VERSION 5.7 ;
  NOWIREEXTENSIONATPIN ON ;
  DIVIDERCHAR "/" ;
  BUSBITCHARS "[]" ;
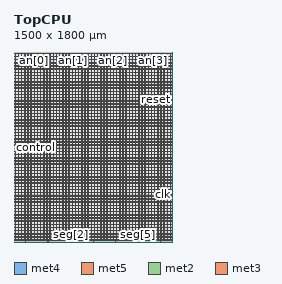
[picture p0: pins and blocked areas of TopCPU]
MACRO TopCPU
  CLASS BLOCK ;
  FOREIGN TopCPU ;
  ORIGIN 0.000 0.000 ;
  SIZE 1500.000 BY 1800.000 ;
  PIN VGND
    DIRECTION INOUT ;
    USE GROUND ;
    PORT
      LAYER met4 ;
        RECT 13.020 10.640 14.620 1787.280 ;
    END
    PORT
      LAYER met4 ;
        RECT 43.020 10.640 44.620 1787.280 ;
    END
    PORT
      LAYER met4 ;
        RECT 73.020 10.640 74.620 1787.280 ;
    END
    PORT
      LAYER met4 ;
        RECT 103.020 10.640 104.620 1787.280 ;
    END
    PORT
      LAYER met4 ;
        RECT 133.020 10.640 134.620 1787.280 ;
    END
    PORT
      LAYER met4 ;
        RECT 163.020 10.640 164.620 1787.280 ;
    END
    PORT
      LAYER met4 ;
        RECT 193.020 10.640 194.620 1787.280 ;
    END
    PORT
      LAYER met4 ;
        RECT 223.020 10.640 224.620 1787.280 ;
    END
    PORT
      LAYER met4 ;
        RECT 253.020 10.640 254.620 1787.280 ;
    END
    PORT
      LAYER met4 ;
        RECT 283.020 10.640 284.620 1787.280 ;
    END
    PORT
      LAYER met4 ;
        RECT 313.020 10.640 314.620 1787.280 ;
    END
    PORT
      LAYER met4 ;
        RECT 343.020 10.640 344.620 1787.280 ;
    END
    PORT
      LAYER met4 ;
        RECT 373.020 10.640 374.620 1787.280 ;
    END
    PORT
      LAYER met4 ;
        RECT 403.020 10.640 404.620 1787.280 ;
    END
    PORT
      LAYER met4 ;
        RECT 433.020 10.640 434.620 1787.280 ;
    END
    PORT
      LAYER met4 ;
        RECT 463.020 10.640 464.620 1787.280 ;
    END
    PORT
      LAYER met4 ;
        RECT 493.020 10.640 494.620 1787.280 ;
    END
    PORT
      LAYER met4 ;
        RECT 523.020 10.640 524.620 1787.280 ;
    END
    PORT
      LAYER met4 ;
        RECT 553.020 10.640 554.620 1787.280 ;
    END
    PORT
      LAYER met4 ;
        RECT 583.020 10.640 584.620 1787.280 ;
    END
    PORT
      LAYER met4 ;
        RECT 613.020 10.640 614.620 1787.280 ;
    END
    PORT
      LAYER met4 ;
        RECT 643.020 10.640 644.620 1787.280 ;
    END
    PORT
      LAYER met4 ;
        RECT 673.020 10.640 674.620 1787.280 ;
    END
    PORT
      LAYER met4 ;
        RECT 703.020 10.640 704.620 1787.280 ;
    END
    PORT
      LAYER met4 ;
        RECT 733.020 10.640 734.620 1787.280 ;
    END
    PORT
      LAYER met4 ;
        RECT 763.020 10.640 764.620 1787.280 ;
    END
    PORT
      LAYER met4 ;
        RECT 793.020 10.640 794.620 1787.280 ;
    END
    PORT
      LAYER met4 ;
        RECT 823.020 10.640 824.620 1787.280 ;
    END
    PORT
      LAYER met4 ;
        RECT 853.020 10.640 854.620 1787.280 ;
    END
    PORT
      LAYER met4 ;
        RECT 883.020 10.640 884.620 1787.280 ;
    END
    PORT
      LAYER met4 ;
        RECT 913.020 10.640 914.620 1787.280 ;
    END
    PORT
      LAYER met4 ;
        RECT 943.020 10.640 944.620 1787.280 ;
    END
    PORT
      LAYER met4 ;
        RECT 973.020 10.640 974.620 1787.280 ;
    END
    PORT
      LAYER met4 ;
        RECT 1003.020 10.640 1004.620 1787.280 ;
    END
    PORT
      LAYER met4 ;
        RECT 1033.020 10.640 1034.620 1787.280 ;
    END
    PORT
      LAYER met4 ;
        RECT 1063.020 10.640 1064.620 1787.280 ;
    END
    PORT
      LAYER met4 ;
        RECT 1093.020 10.640 1094.620 1787.280 ;
    END
    PORT
      LAYER met4 ;
        RECT 1123.020 10.640 1124.620 1787.280 ;
    END
    PORT
      LAYER met4 ;
        RECT 1153.020 10.640 1154.620 1787.280 ;
    END
    PORT
      LAYER met4 ;
        RECT 1183.020 10.640 1184.620 1787.280 ;
    END
    PORT
      LAYER met4 ;
        RECT 1213.020 10.640 1214.620 1787.280 ;
    END
    PORT
      LAYER met4 ;
        RECT 1243.020 10.640 1244.620 1787.280 ;
    END
    PORT
      LAYER met4 ;
        RECT 1273.020 10.640 1274.620 1787.280 ;
    END
    PORT
      LAYER met4 ;
        RECT 1303.020 10.640 1304.620 1787.280 ;
    END
    PORT
      LAYER met4 ;
        RECT 1333.020 10.640 1334.620 1787.280 ;
    END
    PORT
      LAYER met4 ;
        RECT 1363.020 10.640 1364.620 1787.280 ;
    END
    PORT
      LAYER met4 ;
        RECT 1393.020 10.640 1394.620 1787.280 ;
    END
    PORT
      LAYER met4 ;
        RECT 1423.020 10.640 1424.620 1787.280 ;
    END
    PORT
      LAYER met4 ;
        RECT 1453.020 10.640 1454.620 1787.280 ;
    END
    PORT
      LAYER met4 ;
        RECT 1483.020 10.640 1484.620 1787.280 ;
    END
    PORT
      LAYER met5 ;
        RECT 5.280 18.380 1494.320 19.980 ;
    END
    PORT
      LAYER met5 ;
        RECT 5.280 48.380 1494.320 49.980 ;
    END
    PORT
      LAYER met5 ;
        RECT 5.280 78.380 1494.320 79.980 ;
    END
    PORT
      LAYER met5 ;
        RECT 5.280 108.380 1494.320 109.980 ;
    END
    PORT
      LAYER met5 ;
        RECT 5.280 138.380 1494.320 139.980 ;
    END
    PORT
      LAYER met5 ;
        RECT 5.280 168.380 1494.320 169.980 ;
    END
    PORT
      LAYER met5 ;
        RECT 5.280 198.380 1494.320 199.980 ;
    END
    PORT
      LAYER met5 ;
        RECT 5.280 228.380 1494.320 229.980 ;
    END
    PORT
      LAYER met5 ;
        RECT 5.280 258.380 1494.320 259.980 ;
    END
    PORT
      LAYER met5 ;
        RECT 5.280 288.380 1494.320 289.980 ;
    END
    PORT
      LAYER met5 ;
        RECT 5.280 318.380 1494.320 319.980 ;
    END
    PORT
      LAYER met5 ;
        RECT 5.280 348.380 1494.320 349.980 ;
    END
    PORT
      LAYER met5 ;
        RECT 5.280 378.380 1494.320 379.980 ;
    END
    PORT
      LAYER met5 ;
        RECT 5.280 408.380 1494.320 409.980 ;
    END
    PORT
      LAYER met5 ;
        RECT 5.280 438.380 1494.320 439.980 ;
    END
    PORT
      LAYER met5 ;
        RECT 5.280 468.380 1494.320 469.980 ;
    END
    PORT
      LAYER met5 ;
        RECT 5.280 498.380 1494.320 499.980 ;
    END
    PORT
      LAYER met5 ;
        RECT 5.280 528.380 1494.320 529.980 ;
    END
    PORT
      LAYER met5 ;
        RECT 5.280 558.380 1494.320 559.980 ;
    END
    PORT
      LAYER met5 ;
        RECT 5.280 588.380 1494.320 589.980 ;
    END
    PORT
      LAYER met5 ;
        RECT 5.280 618.380 1494.320 619.980 ;
    END
    PORT
      LAYER met5 ;
        RECT 5.280 648.380 1494.320 649.980 ;
    END
    PORT
      LAYER met5 ;
        RECT 5.280 678.380 1494.320 679.980 ;
    END
    PORT
      LAYER met5 ;
        RECT 5.280 708.380 1494.320 709.980 ;
    END
    PORT
      LAYER met5 ;
        RECT 5.280 738.380 1494.320 739.980 ;
    END
    PORT
      LAYER met5 ;
        RECT 5.280 768.380 1494.320 769.980 ;
    END
    PORT
      LAYER met5 ;
        RECT 5.280 798.380 1494.320 799.980 ;
    END
    PORT
      LAYER met5 ;
        RECT 5.280 828.380 1494.320 829.980 ;
    END
    PORT
      LAYER met5 ;
        RECT 5.280 858.380 1494.320 859.980 ;
    END
    PORT
      LAYER met5 ;
        RECT 5.280 888.380 1494.320 889.980 ;
    END
    PORT
      LAYER met5 ;
        RECT 5.280 918.380 1494.320 919.980 ;
    END
    PORT
      LAYER met5 ;
        RECT 5.280 948.380 1494.320 949.980 ;
    END
    PORT
      LAYER met5 ;
        RECT 5.280 978.380 1494.320 979.980 ;
    END
    PORT
      LAYER met5 ;
        RECT 5.280 1008.380 1494.320 1009.980 ;
    END
    PORT
      LAYER met5 ;
        RECT 5.280 1038.380 1494.320 1039.980 ;
    END
    PORT
      LAYER met5 ;
        RECT 5.280 1068.380 1494.320 1069.980 ;
    END
    PORT
      LAYER met5 ;
        RECT 5.280 1098.380 1494.320 1099.980 ;
    END
    PORT
      LAYER met5 ;
        RECT 5.280 1128.380 1494.320 1129.980 ;
    END
    PORT
      LAYER met5 ;
        RECT 5.280 1158.380 1494.320 1159.980 ;
    END
    PORT
      LAYER met5 ;
        RECT 5.280 1188.380 1494.320 1189.980 ;
    END
    PORT
      LAYER met5 ;
        RECT 5.280 1218.380 1494.320 1219.980 ;
    END
    PORT
      LAYER met5 ;
        RECT 5.280 1248.380 1494.320 1249.980 ;
    END
    PORT
      LAYER met5 ;
        RECT 5.280 1278.380 1494.320 1279.980 ;
    END
    PORT
      LAYER met5 ;
        RECT 5.280 1308.380 1494.320 1309.980 ;
    END
    PORT
      LAYER met5 ;
        RECT 5.280 1338.380 1494.320 1339.980 ;
    END
    PORT
      LAYER met5 ;
        RECT 5.280 1368.380 1494.320 1369.980 ;
    END
    PORT
      LAYER met5 ;
        RECT 5.280 1398.380 1494.320 1399.980 ;
    END
    PORT
      LAYER met5 ;
        RECT 5.280 1428.380 1494.320 1429.980 ;
    END
    PORT
      LAYER met5 ;
        RECT 5.280 1458.380 1494.320 1459.980 ;
    END
    PORT
      LAYER met5 ;
        RECT 5.280 1488.380 1494.320 1489.980 ;
    END
    PORT
      LAYER met5 ;
        RECT 5.280 1518.380 1494.320 1519.980 ;
    END
    PORT
      LAYER met5 ;
        RECT 5.280 1548.380 1494.320 1549.980 ;
    END
    PORT
      LAYER met5 ;
        RECT 5.280 1578.380 1494.320 1579.980 ;
    END
    PORT
      LAYER met5 ;
        RECT 5.280 1608.380 1494.320 1609.980 ;
    END
    PORT
      LAYER met5 ;
        RECT 5.280 1638.380 1494.320 1639.980 ;
    END
    PORT
      LAYER met5 ;
        RECT 5.280 1668.380 1494.320 1669.980 ;
    END
    PORT
      LAYER met5 ;
        RECT 5.280 1698.380 1494.320 1699.980 ;
    END
    PORT
      LAYER met5 ;
        RECT 5.280 1728.380 1494.320 1729.980 ;
    END
    PORT
      LAYER met5 ;
        RECT 5.280 1758.380 1494.320 1759.980 ;
    END
  END VGND
  PIN VPWR
    DIRECTION INOUT ;
    USE POWER ;
    PORT
      LAYER met4 ;
        RECT 9.720 10.640 11.320 1787.280 ;
    END
    PORT
      LAYER met4 ;
        RECT 39.720 10.640 41.320 1787.280 ;
    END
    PORT
      LAYER met4 ;
        RECT 69.720 10.640 71.320 1787.280 ;
    END
    PORT
      LAYER met4 ;
        RECT 99.720 10.640 101.320 1787.280 ;
    END
    PORT
      LAYER met4 ;
        RECT 129.720 10.640 131.320 1787.280 ;
    END
    PORT
      LAYER met4 ;
        RECT 159.720 10.640 161.320 1787.280 ;
    END
    PORT
      LAYER met4 ;
        RECT 189.720 10.640 191.320 1787.280 ;
    END
    PORT
      LAYER met4 ;
        RECT 219.720 10.640 221.320 1787.280 ;
    END
    PORT
      LAYER met4 ;
        RECT 249.720 10.640 251.320 1787.280 ;
    END
    PORT
      LAYER met4 ;
        RECT 279.720 10.640 281.320 1787.280 ;
    END
    PORT
      LAYER met4 ;
        RECT 309.720 10.640 311.320 1787.280 ;
    END
    PORT
      LAYER met4 ;
        RECT 339.720 10.640 341.320 1787.280 ;
    END
    PORT
      LAYER met4 ;
        RECT 369.720 10.640 371.320 1787.280 ;
    END
    PORT
      LAYER met4 ;
        RECT 399.720 10.640 401.320 1787.280 ;
    END
    PORT
      LAYER met4 ;
        RECT 429.720 10.640 431.320 1787.280 ;
    END
    PORT
      LAYER met4 ;
        RECT 459.720 10.640 461.320 1787.280 ;
    END
    PORT
      LAYER met4 ;
        RECT 489.720 10.640 491.320 1787.280 ;
    END
    PORT
      LAYER met4 ;
        RECT 519.720 10.640 521.320 1787.280 ;
    END
    PORT
      LAYER met4 ;
        RECT 549.720 10.640 551.320 1787.280 ;
    END
    PORT
      LAYER met4 ;
        RECT 579.720 10.640 581.320 1787.280 ;
    END
    PORT
      LAYER met4 ;
        RECT 609.720 10.640 611.320 1787.280 ;
    END
    PORT
      LAYER met4 ;
        RECT 639.720 10.640 641.320 1787.280 ;
    END
    PORT
      LAYER met4 ;
        RECT 669.720 10.640 671.320 1787.280 ;
    END
    PORT
      LAYER met4 ;
        RECT 699.720 10.640 701.320 1787.280 ;
    END
    PORT
      LAYER met4 ;
        RECT 729.720 10.640 731.320 1787.280 ;
    END
    PORT
      LAYER met4 ;
        RECT 759.720 10.640 761.320 1787.280 ;
    END
    PORT
      LAYER met4 ;
        RECT 789.720 10.640 791.320 1787.280 ;
    END
    PORT
      LAYER met4 ;
        RECT 819.720 10.640 821.320 1787.280 ;
    END
    PORT
      LAYER met4 ;
        RECT 849.720 10.640 851.320 1787.280 ;
    END
    PORT
      LAYER met4 ;
        RECT 879.720 10.640 881.320 1787.280 ;
    END
    PORT
      LAYER met4 ;
        RECT 909.720 10.640 911.320 1787.280 ;
    END
    PORT
      LAYER met4 ;
        RECT 939.720 10.640 941.320 1787.280 ;
    END
    PORT
      LAYER met4 ;
        RECT 969.720 10.640 971.320 1787.280 ;
    END
    PORT
      LAYER met4 ;
        RECT 999.720 10.640 1001.320 1787.280 ;
    END
    PORT
      LAYER met4 ;
        RECT 1029.720 10.640 1031.320 1787.280 ;
    END
    PORT
      LAYER met4 ;
        RECT 1059.720 10.640 1061.320 1787.280 ;
    END
    PORT
      LAYER met4 ;
        RECT 1089.720 10.640 1091.320 1787.280 ;
    END
    PORT
      LAYER met4 ;
        RECT 1119.720 10.640 1121.320 1787.280 ;
    END
    PORT
      LAYER met4 ;
        RECT 1149.720 10.640 1151.320 1787.280 ;
    END
    PORT
      LAYER met4 ;
        RECT 1179.720 10.640 1181.320 1787.280 ;
    END
    PORT
      LAYER met4 ;
        RECT 1209.720 10.640 1211.320 1787.280 ;
    END
    PORT
      LAYER met4 ;
        RECT 1239.720 10.640 1241.320 1787.280 ;
    END
    PORT
      LAYER met4 ;
        RECT 1269.720 10.640 1271.320 1787.280 ;
    END
    PORT
      LAYER met4 ;
        RECT 1299.720 10.640 1301.320 1787.280 ;
    END
    PORT
      LAYER met4 ;
        RECT 1329.720 10.640 1331.320 1787.280 ;
    END
    PORT
      LAYER met4 ;
        RECT 1359.720 10.640 1361.320 1787.280 ;
    END
    PORT
      LAYER met4 ;
        RECT 1389.720 10.640 1391.320 1787.280 ;
    END
    PORT
      LAYER met4 ;
        RECT 1419.720 10.640 1421.320 1787.280 ;
    END
    PORT
      LAYER met4 ;
        RECT 1449.720 10.640 1451.320 1787.280 ;
    END
    PORT
      LAYER met4 ;
        RECT 1479.720 10.640 1481.320 1787.280 ;
    END
    PORT
      LAYER met5 ;
        RECT 5.280 15.080 1494.320 16.680 ;
    END
    PORT
      LAYER met5 ;
        RECT 5.280 45.080 1494.320 46.680 ;
    END
    PORT
      LAYER met5 ;
        RECT 5.280 75.080 1494.320 76.680 ;
    END
    PORT
      LAYER met5 ;
        RECT 5.280 105.080 1494.320 106.680 ;
    END
    PORT
      LAYER met5 ;
        RECT 5.280 135.080 1494.320 136.680 ;
    END
    PORT
      LAYER met5 ;
        RECT 5.280 165.080 1494.320 166.680 ;
    END
    PORT
      LAYER met5 ;
        RECT 5.280 195.080 1494.320 196.680 ;
    END
    PORT
      LAYER met5 ;
        RECT 5.280 225.080 1494.320 226.680 ;
    END
    PORT
      LAYER met5 ;
        RECT 5.280 255.080 1494.320 256.680 ;
    END
    PORT
      LAYER met5 ;
        RECT 5.280 285.080 1494.320 286.680 ;
    END
    PORT
      LAYER met5 ;
        RECT 5.280 315.080 1494.320 316.680 ;
    END
    PORT
      LAYER met5 ;
        RECT 5.280 345.080 1494.320 346.680 ;
    END
    PORT
      LAYER met5 ;
        RECT 5.280 375.080 1494.320 376.680 ;
    END
    PORT
      LAYER met5 ;
        RECT 5.280 405.080 1494.320 406.680 ;
    END
    PORT
      LAYER met5 ;
        RECT 5.280 435.080 1494.320 436.680 ;
    END
    PORT
      LAYER met5 ;
        RECT 5.280 465.080 1494.320 466.680 ;
    END
    PORT
      LAYER met5 ;
        RECT 5.280 495.080 1494.320 496.680 ;
    END
    PORT
      LAYER met5 ;
        RECT 5.280 525.080 1494.320 526.680 ;
    END
    PORT
      LAYER met5 ;
        RECT 5.280 555.080 1494.320 556.680 ;
    END
    PORT
      LAYER met5 ;
        RECT 5.280 585.080 1494.320 586.680 ;
    END
    PORT
      LAYER met5 ;
        RECT 5.280 615.080 1494.320 616.680 ;
    END
    PORT
      LAYER met5 ;
        RECT 5.280 645.080 1494.320 646.680 ;
    END
    PORT
      LAYER met5 ;
        RECT 5.280 675.080 1494.320 676.680 ;
    END
    PORT
      LAYER met5 ;
        RECT 5.280 705.080 1494.320 706.680 ;
    END
    PORT
      LAYER met5 ;
        RECT 5.280 735.080 1494.320 736.680 ;
    END
    PORT
      LAYER met5 ;
        RECT 5.280 765.080 1494.320 766.680 ;
    END
    PORT
      LAYER met5 ;
        RECT 5.280 795.080 1494.320 796.680 ;
    END
    PORT
      LAYER met5 ;
        RECT 5.280 825.080 1494.320 826.680 ;
    END
    PORT
      LAYER met5 ;
        RECT 5.280 855.080 1494.320 856.680 ;
    END
    PORT
      LAYER met5 ;
        RECT 5.280 885.080 1494.320 886.680 ;
    END
    PORT
      LAYER met5 ;
        RECT 5.280 915.080 1494.320 916.680 ;
    END
    PORT
      LAYER met5 ;
        RECT 5.280 945.080 1494.320 946.680 ;
    END
    PORT
      LAYER met5 ;
        RECT 5.280 975.080 1494.320 976.680 ;
    END
    PORT
      LAYER met5 ;
        RECT 5.280 1005.080 1494.320 1006.680 ;
    END
    PORT
      LAYER met5 ;
        RECT 5.280 1035.080 1494.320 1036.680 ;
    END
    PORT
      LAYER met5 ;
        RECT 5.280 1065.080 1494.320 1066.680 ;
    END
    PORT
      LAYER met5 ;
        RECT 5.280 1095.080 1494.320 1096.680 ;
    END
    PORT
      LAYER met5 ;
        RECT 5.280 1125.080 1494.320 1126.680 ;
    END
    PORT
      LAYER met5 ;
        RECT 5.280 1155.080 1494.320 1156.680 ;
    END
    PORT
      LAYER met5 ;
        RECT 5.280 1185.080 1494.320 1186.680 ;
    END
    PORT
      LAYER met5 ;
        RECT 5.280 1215.080 1494.320 1216.680 ;
    END
    PORT
      LAYER met5 ;
        RECT 5.280 1245.080 1494.320 1246.680 ;
    END
    PORT
      LAYER met5 ;
        RECT 5.280 1275.080 1494.320 1276.680 ;
    END
    PORT
      LAYER met5 ;
        RECT 5.280 1305.080 1494.320 1306.680 ;
    END
    PORT
      LAYER met5 ;
        RECT 5.280 1335.080 1494.320 1336.680 ;
    END
    PORT
      LAYER met5 ;
        RECT 5.280 1365.080 1494.320 1366.680 ;
    END
    PORT
      LAYER met5 ;
        RECT 5.280 1395.080 1494.320 1396.680 ;
    END
    PORT
      LAYER met5 ;
        RECT 5.280 1425.080 1494.320 1426.680 ;
    END
    PORT
      LAYER met5 ;
        RECT 5.280 1455.080 1494.320 1456.680 ;
    END
    PORT
      LAYER met5 ;
        RECT 5.280 1485.080 1494.320 1486.680 ;
    END
    PORT
      LAYER met5 ;
        RECT 5.280 1515.080 1494.320 1516.680 ;
    END
    PORT
      LAYER met5 ;
        RECT 5.280 1545.080 1494.320 1546.680 ;
    END
    PORT
      LAYER met5 ;
        RECT 5.280 1575.080 1494.320 1576.680 ;
    END
    PORT
      LAYER met5 ;
        RECT 5.280 1605.080 1494.320 1606.680 ;
    END
    PORT
      LAYER met5 ;
        RECT 5.280 1635.080 1494.320 1636.680 ;
    END
    PORT
      LAYER met5 ;
        RECT 5.280 1665.080 1494.320 1666.680 ;
    END
    PORT
      LAYER met5 ;
        RECT 5.280 1695.080 1494.320 1696.680 ;
    END
    PORT
      LAYER met5 ;
        RECT 5.280 1725.080 1494.320 1726.680 ;
    END
    PORT
      LAYER met5 ;
        RECT 5.280 1755.080 1494.320 1756.680 ;
    END
    PORT
      LAYER met5 ;
        RECT 5.280 1785.080 1494.320 1786.680 ;
    END
  END VPWR
  PIN an[0]
    DIRECTION OUTPUT ;
    USE SIGNAL ;
    PORT
      LAYER met2 ;
        RECT 187.310 1796.000 187.590 1800.000 ;
    END
  END an[0]
  PIN an[1]
    DIRECTION OUTPUT ;
    USE SIGNAL ;
    PORT
      LAYER met2 ;
        RECT 562.210 1796.000 562.490 1800.000 ;
    END
  END an[1]
  PIN an[2]
    DIRECTION OUTPUT ;
    USE SIGNAL ;
    PORT
      LAYER met2 ;
        RECT 937.110 1796.000 937.390 1800.000 ;
    END
  END an[2]
  PIN an[3]
    DIRECTION OUTPUT ;
    USE SIGNAL ;
    PORT
      LAYER met2 ;
        RECT 1312.010 1796.000 1312.290 1800.000 ;
    END
  END an[3]
  PIN clk
    DIRECTION INPUT ;
    USE SIGNAL ;
    ANTENNAGATEAREA 0.852000 ;
    ANTENNADIFFAREA 0.434700 ;
    PORT
      LAYER met3 ;
        RECT 1496.000 448.840 1500.000 449.440 ;
    END
  END clk
  PIN control
    DIRECTION INPUT ;
    USE SIGNAL ;
    ANTENNAGATEAREA 0.990000 ;
    ANTENNADIFFAREA 0.434700 ;
    PORT
      LAYER met3 ;
        RECT 0.000 899.000 4.000 899.600 ;
    END
  END control
  PIN reset
    DIRECTION INPUT ;
    USE SIGNAL ;
    ANTENNAGATEAREA 0.990000 ;
    ANTENNADIFFAREA 0.434700 ;
    PORT
      LAYER met3 ;
        RECT 1496.000 1349.160 1500.000 1349.760 ;
    END
  END reset
  PIN seg[0]
    DIRECTION OUTPUT ;
    USE SIGNAL ;
    ANTENNADIFFAREA 0.340600 ;
    PORT
      LAYER met2 ;
        RECT 108.190 0.000 108.470 4.000 ;
    END
  END seg[0]
  PIN seg[1]
    DIRECTION OUTPUT ;
    USE SIGNAL ;
    ANTENNADIFFAREA 0.340600 ;
    PORT
      LAYER met2 ;
        RECT 322.090 0.000 322.370 4.000 ;
    END
  END seg[1]
  PIN seg[2]
    DIRECTION OUTPUT ;
    USE SIGNAL ;
    ANTENNADIFFAREA 0.340600 ;
    PORT
      LAYER met2 ;
        RECT 535.990 0.000 536.270 4.000 ;
    END
  END seg[2]
  PIN seg[3]
    DIRECTION OUTPUT ;
    USE SIGNAL ;
    ANTENNADIFFAREA 0.340600 ;
    PORT
      LAYER met2 ;
        RECT 749.890 0.000 750.170 4.000 ;
    END
  END seg[3]
  PIN seg[4]
    DIRECTION OUTPUT ;
    USE SIGNAL ;
    ANTENNADIFFAREA 0.340600 ;
    PORT
      LAYER met2 ;
        RECT 963.790 0.000 964.070 4.000 ;
    END
  END seg[4]
  PIN seg[5]
    DIRECTION OUTPUT ;
    USE SIGNAL ;
    ANTENNADIFFAREA 0.340600 ;
    PORT
      LAYER met2 ;
        RECT 1177.690 0.000 1177.970 4.000 ;
    END
  END seg[5]
  PIN seg[6]
    DIRECTION OUTPUT ;
    USE SIGNAL ;
    ANTENNADIFFAREA 0.340600 ;
    PORT
      LAYER met2 ;
        RECT 1391.590 0.000 1391.870 4.000 ;
    END
  END seg[6]
  OBS
      LAYER nwell ;
        RECT 5.330 10.795 1494.270 1787.230 ;
      LAYER li1 ;
        RECT 5.520 10.795 1494.080 1787.125 ;
      LAYER met1 ;
        RECT 5.520 10.640 1494.080 1787.280 ;
      LAYER met2 ;
        RECT 6.530 1795.720 187.030 1796.000 ;
        RECT 187.870 1795.720 561.930 1796.000 ;
        RECT 562.770 1795.720 936.830 1796.000 ;
        RECT 937.670 1795.720 1311.730 1796.000 ;
        RECT 1312.570 1795.720 1492.610 1796.000 ;
        RECT 6.530 4.280 1492.610 1795.720 ;
        RECT 6.530 4.000 107.910 4.280 ;
        RECT 108.750 4.000 321.810 4.280 ;
        RECT 322.650 4.000 535.710 4.280 ;
        RECT 536.550 4.000 749.610 4.280 ;
        RECT 750.450 4.000 963.510 4.280 ;
        RECT 964.350 4.000 1177.410 4.280 ;
        RECT 1178.250 4.000 1391.310 4.280 ;
        RECT 1392.150 4.000 1492.610 4.280 ;
      LAYER met3 ;
        RECT 4.000 1350.160 1496.000 1787.205 ;
        RECT 4.000 1348.760 1495.600 1350.160 ;
        RECT 4.000 900.000 1496.000 1348.760 ;
        RECT 4.400 898.600 1496.000 900.000 ;
        RECT 4.000 449.840 1496.000 898.600 ;
        RECT 4.000 448.440 1495.600 449.840 ;
        RECT 4.000 10.715 1496.000 448.440 ;
      LAYER met4 ;
        RECT 735.375 61.375 759.320 449.985 ;
        RECT 761.720 61.375 762.620 449.985 ;
        RECT 765.020 61.375 789.320 449.985 ;
        RECT 791.720 61.375 792.620 449.985 ;
        RECT 795.020 61.375 819.320 449.985 ;
        RECT 821.720 61.375 822.620 449.985 ;
        RECT 825.020 61.375 849.320 449.985 ;
        RECT 851.720 61.375 852.620 449.985 ;
        RECT 855.020 61.375 879.320 449.985 ;
        RECT 881.720 61.375 882.620 449.985 ;
        RECT 885.020 61.375 909.320 449.985 ;
        RECT 911.720 61.375 912.620 449.985 ;
        RECT 915.020 61.375 939.320 449.985 ;
        RECT 941.720 61.375 942.620 449.985 ;
        RECT 945.020 61.375 969.320 449.985 ;
        RECT 971.720 61.375 972.620 449.985 ;
        RECT 975.020 61.375 999.320 449.985 ;
        RECT 1001.720 61.375 1002.620 449.985 ;
        RECT 1005.020 61.375 1029.320 449.985 ;
        RECT 1031.720 61.375 1032.620 449.985 ;
        RECT 1035.020 61.375 1059.320 449.985 ;
        RECT 1061.720 61.375 1062.620 449.985 ;
        RECT 1065.020 61.375 1089.320 449.985 ;
        RECT 1091.720 61.375 1092.620 449.985 ;
        RECT 1095.020 61.375 1119.320 449.985 ;
        RECT 1121.720 61.375 1122.620 449.985 ;
        RECT 1125.020 61.375 1149.320 449.985 ;
        RECT 1151.720 61.375 1152.620 449.985 ;
        RECT 1155.020 61.375 1179.320 449.985 ;
        RECT 1181.720 61.375 1182.620 449.985 ;
        RECT 1185.020 61.375 1209.320 449.985 ;
        RECT 1211.720 61.375 1212.620 449.985 ;
        RECT 1215.020 61.375 1239.320 449.985 ;
        RECT 1241.720 61.375 1242.620 449.985 ;
        RECT 1245.020 61.375 1269.320 449.985 ;
        RECT 1271.720 61.375 1272.620 449.985 ;
        RECT 1275.020 61.375 1299.320 449.985 ;
        RECT 1301.720 61.375 1302.620 449.985 ;
        RECT 1305.020 61.375 1329.320 449.985 ;
        RECT 1331.720 61.375 1332.620 449.985 ;
        RECT 1335.020 61.375 1359.320 449.985 ;
        RECT 1361.720 61.375 1362.620 449.985 ;
        RECT 1365.020 61.375 1389.320 449.985 ;
        RECT 1391.720 61.375 1392.620 449.985 ;
        RECT 1395.020 61.375 1419.320 449.985 ;
        RECT 1421.720 61.375 1422.620 449.985 ;
        RECT 1425.020 61.375 1449.320 449.985 ;
        RECT 1451.720 61.375 1452.620 449.985 ;
        RECT 1455.020 61.375 1478.145 449.985 ;
  END
END TopCPU
END LIBRARY

